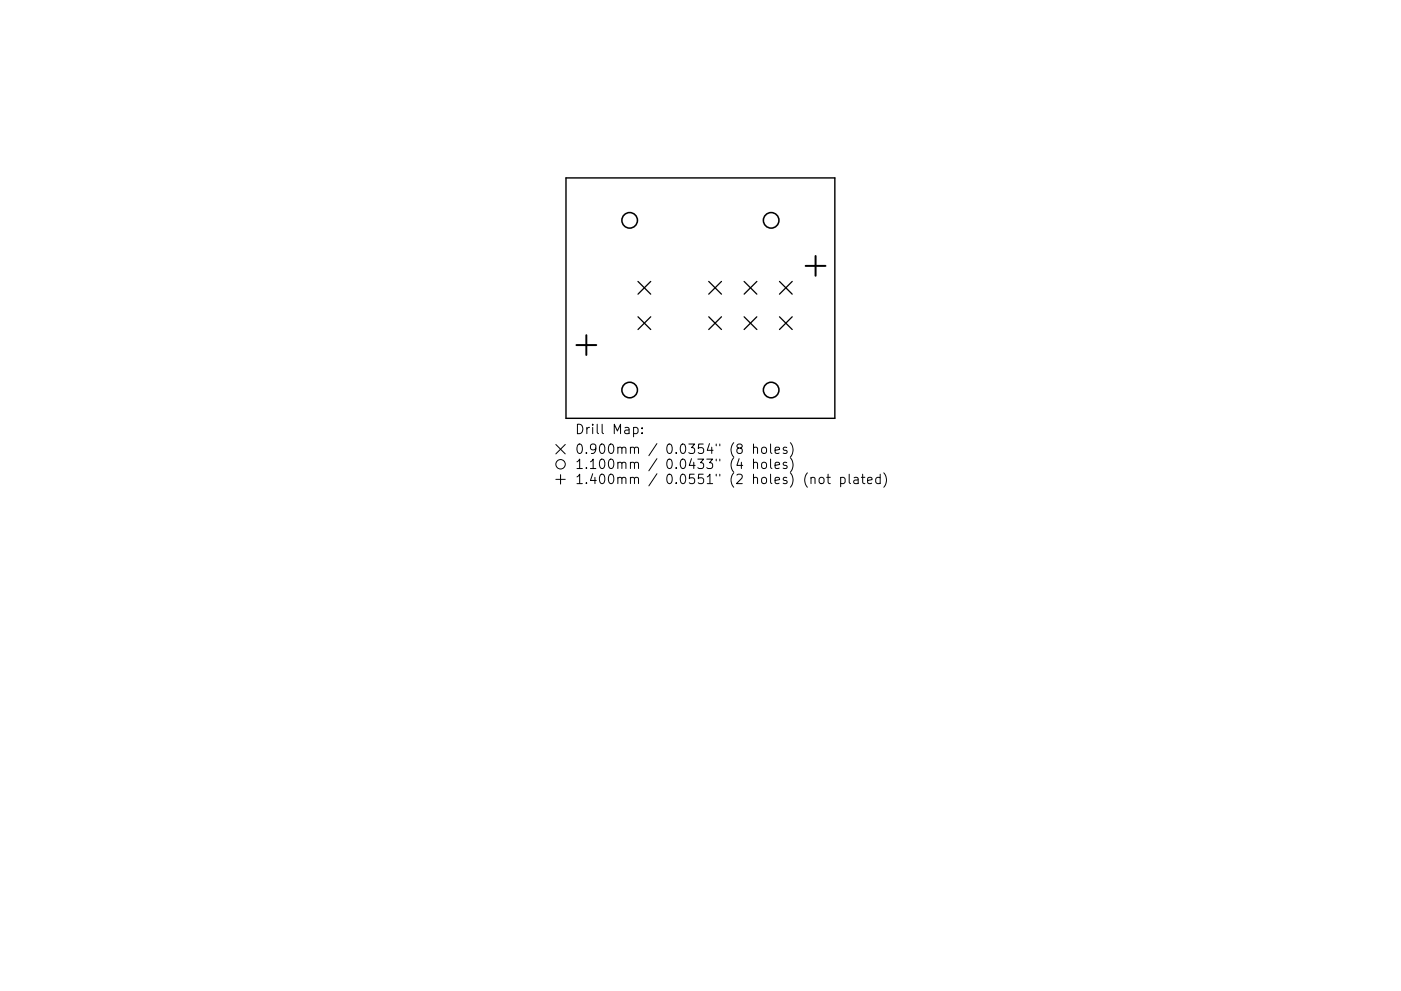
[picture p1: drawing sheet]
<svg xmlns="http://www.w3.org/2000/svg" width="297mm" height="210mm" viewBox="0 0 297 210" stroke-linecap="round" stroke-linejoin="round" font-family="sans-serif">
<defs><g id="words">
<g font-size="2.8">
<text x="121.8" y="92.1">Drill Map:</text>
<text x="121.8" y="96.3">0.900mm / 0.0354&quot; (8 holes)</text>
<text x="121.8" y="99.5">1.100mm / 0.0433&quot; (4 holes)</text>
<text x="121.8" y="102.7">1.400mm / 0.0551&quot; (2 holes) (not plated)</text>
</g>
</g></defs>
<path d="M120 37.7h57v51.1h-57z" fill="none" stroke="#000" stroke-width=".3"/>
<g fill="none" stroke="#000" stroke-width=".27">
<path d="M135.3 59.7l2.7 2.7M138 59.7l-2.7 2.7M150.3 59.7l2.7 2.7M153 59.7l-2.7 2.7M157.8 59.7l2.7 2.7M160.5 59.7l-2.7 2.7M165.3 59.7l2.7 2.7M168 59.7l-2.7 2.7M135.3 67.2l2.7 2.7M138 67.2l-2.7 2.7M150.3 67.2l2.7 2.7M153 67.2l-2.7 2.7"/>
<path d="M157.8 67.2l2.7 2.7M160.5 67.2l-2.7 2.7M165.3 67.2l2.7 2.7M168 67.2l-2.7 2.7"/>
</g>
<g fill="none" stroke="#000" stroke-width=".33">
<circle cx="133.5" cy="46.8" r="1.65"/>
<circle cx="163.5" cy="46.8" r="1.65"/>
<circle cx="133.5" cy="82.8" r="1.65"/>
<circle cx="163.5" cy="82.8" r="1.65"/>
</g>
<path d="M170.8 56.4h4.2M172.9 54.3v4.2M122.2 73.2h4.2M124.3 71.1v4.2" fill="none" stroke="#000" stroke-width=".42"/>
<g fill="none" stroke="#000" stroke-width=".21">
<path d="M117.8 94.3l2 2M119.8 94.3l-2 2M134.3 90.8l.6-.1 .4 .4v.5l-.2 .3h-.8M136.1 91.8v.2M136.1 90.8v.2M159.8 95.1a.5 .5 0 0 1 .8 .1v1M159.8 98.3a.5 .5 0 0 1 .8 .1v1M159.8 94.2v2M159.8 97.4v2M161.6 95.1l.3-.2 .5 .2 .1 .7-.2 .3-.4 .1-.3-.2zM161.6 98.3l.3-.2 .5 .2 .1 .7-.2 .3-.4 .1-.3-.2zM163.4 94.2v1.7l.3 .3"/>
<path d="M163.4 97.4v1.7l.3 .3M164.3 95.5l1-.1-.1-.4-.6-.1-.3 .3 .1 .9h.8M164.3 98.7l1-.1-.1-.4-.6-.1-.3 .3 .1 .9h.8M166.8 95l-.5-.1-.3 .3 .1 .2 .7 .2v.5h-.8M166.8 98.2l-.5-.1-.3 .3 .1 .2 .7 .2v.5h-.8M167.6 93.9a2.29 2.29 0 0 1 0 3.1M167.6 97.1a2.29 2.29 0 0 1 0 3.1M117.8 101.7h2M118.8 100.7v2M171.9 101.5a.5 .5 0 0 1 .9 .1v1M173.8 101.5l.2-.2 .6 .2 .1 .7-.2 .3-.5 .1-.2-.2zM175.3 101.3h.7"/>
<path d="M175.6 100.6v1.7l.1 .2 .3 .1M178.2 101.4l.6-.1 .4 .4v.5l-.2 .3h-.8M178.2 101.3v2M180 100.6v1.7l.3 .3M181.1 101.4h.8v1.2M181.9 101.8h-.6a.39 .39 0 0 0-.3 .4 .39 .39 0 0 0 .3 .4l.6-.1M182.6 101.3h.8M182.9 100.6v1.7l.1 .2 .4 .1M183.9 101.9l1-.1-.1-.4-.6-.1-.3 .3 .1 .9h.8M186.6 101.4l-.6-.1-.3 .4v.5l.2 .3h.7M186.6 100.6v2M187.4 100.3a2.29 2.29 0 0 1 0 3.1"/>
<circle cx="118.8" cy="98.5" r="1"/>
</g>
<use href="#words"/>
</svg>
